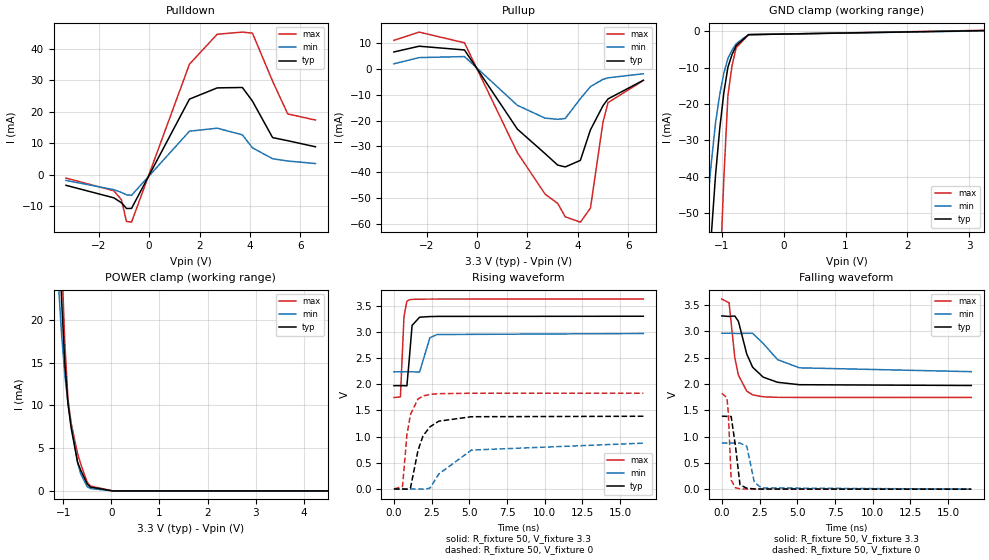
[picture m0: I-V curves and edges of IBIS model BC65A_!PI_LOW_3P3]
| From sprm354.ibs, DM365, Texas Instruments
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|   Model Cell BC65A_!PI_LOW_3P3
|BC1833DV65ATHYPBFZP_!PI_LOW_3P3
[Model]   BC65A_!PI_LOW_3P3
Model_type   I/O
Polarity   Non-Inverting
Enable   Active-Low
Vinl =  0.8V
Vinh =  2V
Cref =  15pF
Rref =  100.00M
Vref =  0V
Vmeas =  1.65
C_comp   1.512681p   1.336608p   1.607201p
[Model Spec]
Vinl   0.8V   0.8V   0.8V
Vinh   2V   2V   2V
[Temperature Range]   25   125   -40
[Voltage Range]   3.3   2.97   3.63
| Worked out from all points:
|   slope of the pulldown table from 0 to 0.495 V, typ, clamps not added: 56.1 ohm
|   slope of the pullup table from 0 to 0.495 V, typ, clamps not added: 64.3 ohm
|   GND clamp passes 1 mA (typ) near -0.57 V on its own axis
|   POWER clamp passes 1 mA (typ) near -0.52 V on its own axis
|   rising waveform, R_fixture 50, V_fixture 3.3: 20-80 % time 186ps typ, 268ps min, 141ps max; typ from 1.97 V to 3.3 V
|   rising waveform, R_fixture 50, V_fixture 0: 20-80 % time 866ps typ, 1.9ns min, 463ps max; typ from 0 V to 1.39 V
|   falling waveform, R_fixture 50, V_fixture 3.3: 20-80 % time 1.03ns typ, 1.61ns min, 559ps max; typ from 3.3 V to 1.97 V
|   falling waveform, R_fixture 50, V_fixture 0: 20-80 % time 211ps typ, 346ps min, 142ps max; typ from 1.39 V to 0 V
[POWER_clamp]
|   voltage   I(typ)   I(min)   I(max)
-3.3V     617.8mA    728.2mA    693.2mA
-1.1V     32.36mA    24.41mA    41.14mA
-1.033V   22.42mA    18.36mA    27.55mA
-966.7mV  15.04mA    13.64mA    17.42mA
-900mV    10.21mA    10.27mA    10.75mA
-833.3mV  7.343mA    7.736mA    7.918mA
-700mV    3.35mA     3.291mA    4.364mA
-633.3mV  2.402mA    1.963mA    3.125mA
-500mV    813.1uA    500.1uA    1.004mA
-433.3mV  446.7uA    279uA      570.4uA
33.33mV   0A         0A         0A
6.6V      0A         0A         0A
[Pulldown]
|   voltage   I(typ)   I(min)   I(max)
-3.3V     -3.312mA   -1.764mA   -1.021mA
-1.4V     -7.283mA   -4.687mA   -5.038mA
-1.1V     -8.83mA    -5.573mA   -7.893mA
-900mV    -10.65mA   -6.307mA   -14.74mA
-700mV    -10.64mA   -6.484mA   -15mA
1.6V      24.01mA    13.84mA    35.08mA
2.7V      27.57mA    14.8mA     44.57mA
3.7V      27.7mA     12.68mA    45.26mA
4.1V      23.38mA    8.578mA    44.92mA
4.9V      11.81mA    5.118mA    29.68mA
5.5V      10.83mA    4.397mA    19.31mA
6.6V      8.906mA    3.589mA    17.38mA
[Pullup]
|   voltage   I(typ)   I(min)   I(max)
-3.3V     6.54mA     1.969mA    11.03mA
-2.3V     8.757mA    4.357mA    14.22mA
-500mV    7.317mA    4.758mA    10.08mA
1.6V      -23.29mA   -14.09mA   -32.38mA
2.7V      -32.76mA   -19.04mA   -48.43mA
3.2V      -37.19mA   -19.48mA   -51.99mA
3.5V      -37.9mA    -19.18mA   -57.17mA
4.1V      -35.37mA   -11.52mA   -59.26mA
4.5V      -23.57mA   -6.848mA   -53.81mA
5V        -14.2mA    -4.028mA   -20.44mA
5.2V      -11.59mA   -3.459mA   -13.01mA
6.6V      -4.403mA   -1.883mA   -4.482mA
[GND_clamp]
|   voltage   I(typ)   I(min)   I(max)
-3.3V     -675.4mA   -720mA     -1.407A
-1.3V     -90.36mA   -60.41mA   -217.3mA
-1.233V   -72.63mA   -47.73mA   -178.1mA
-1.167V   -55.68mA   -35.96mA   -139.7mA
-1.1V     -39.52mA   -25.11mA   -102.1mA
-1.033V   -26.87mA   -17.46mA   -68.92mA
-966.7mV  -17mA      -11.58mA   -40.75mA
-900mV    -9.882mA   -7.454mA   -17.64mA
-833.3mV  -6.396mA   -5.18mA    -9.425mA
-766.7mV  -3.95mA    -3.425mA   -4.522mA
-566.7mV  -952.9uA   -925.9uA   -953.8uA
3.233V    154.8uA    91.52uA    247.5uA
[Ramp]
| variable   typ   min   max
dV/dt_f  0.7941831/1.024705n   0.4396363/1.616067n   1.127286/0.5580922n
dV/dt_r  0.8359851/0.8652909n  0.5292419/1.919135n   1.099152/0.4622589n
R_load = 50
[Rising Waveform]
R_fixture = 50
V_fixture = 3.3
V_fixture_min = 2.97
V_fixture_max = 3.63
|   time   V(typ)   V(min)   V(max)
0s        1.972V     2.235V     1.745V
432ps     1.972V     2.235V     1.758V
668ps     1.972V     2.235V     3.295V
860ps     1.968V     2.235V     3.58V
1.004ns   2.43V      2.235V     3.608V
1.204ns   3.121V     2.235V     3.618V
1.704ns   3.278V     2.234V     3.622V
2.384ns   3.29V      2.885V     3.623V
2.86ns    3.293V     2.947V     3.623V
16.54ns   3.296V     2.967V     3.624V
[Rising Waveform]
R_fixture = 50
V_fixture = 0
V_fixture_min = 0
V_fixture_max = 0
|   time   V(typ)   V(min)   V(max)
0s        8.912uV    -807.8nV   16.94uV
572ps     1.624uV    8.297uV    49.22mV
860ps     -3.219mV   6.647uV    1.026V
1.1ns     21.45mV    5.469uV    1.425V
1.596ns   734.4mV    -88.98uV   1.717V
1.928ns   1.012V     -2.883mV   1.775V
2.384ns   1.185V     13.6mV     1.805V
2.976ns   1.294V     285.9mV    1.819V
5.14ns    1.379V     742.6mV    1.827V
16.54ns   1.388V     874.8mV    1.827V
[Falling Waveform]
R_fixture = 50
V_fixture = 3.3
V_fixture_min = 2.97
V_fixture_max = 3.63
|   time   V(typ)   V(min)   V(max)
0s        3.296V     2.967V     3.616V
480ps     3.285V     2.967V     3.546V
860ps     3.294V     2.963V     2.501V
1.1ns     3.192V     2.961V     2.169V
1.652ns   2.57V      2.965V     1.865V
2.04ns    2.32V      2.965V     1.794V
2.74ns    2.131V     2.772V     1.757V
3.692ns   2.033V     2.465V     1.747V
5.14ns    1.987V     2.308V     1.745V
16.54ns   1.972V     2.235V     1.745V
[Falling Waveform]
R_fixture = 50
V_fixture = 0
V_fixture_min = 0
V_fixture_max = 0
|   time   V(typ)   V(min)   V(max)
0s        1.388V     877.8mV    1.822V
336ps     1.385V     877.7mV    1.743V
432ps     1.384V     877.7mV    1.441V
620ps     1.381V     877.2mV    172.2mV
908ps     809.5mV    875.9mV    24.9mV
1.204ns   82.39mV    876mV      6.734mV
1.652ns   18.4mV     819.3mV    1.196mV
2.152ns   5.684mV    135.4mV    262.7uV
2.62ns    2.536mV    24.01mV    81.97uV
16.54ns   172.5nV    123uV      146.2nV
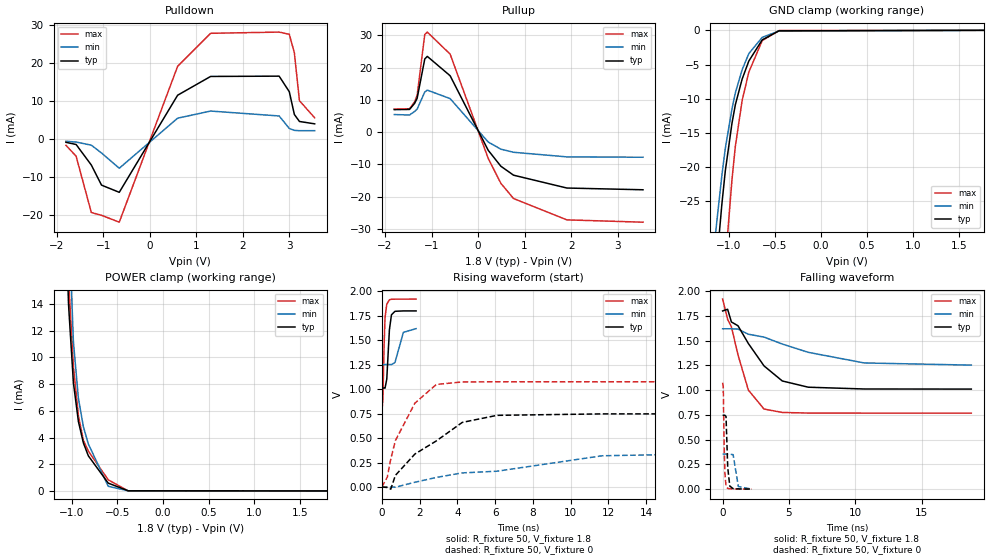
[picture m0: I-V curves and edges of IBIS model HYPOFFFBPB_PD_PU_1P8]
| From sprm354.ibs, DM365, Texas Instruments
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|   Model Cell HYPOFFFBPB_PD_PU_1P8
|BQ1865ACTHYPOFFFBPB_PD_PU_1P8
[Model]   HYPOFFFBPB_PD_PU_1P8
Model_type   I/O
Polarity   Non-Inverting
Enable   Active-Low
Vinl =  0.63V
Vinh =  1.17V
Cref =  15pF
Rref =  100.00M
Vref =  0V
Vmeas =  0.9
C_comp   2.929246p   0.7331204p   5.041237p
[Model Spec]
Vinl   0.63   0.567   0.6720
Vinh   1.17   1.053   1.2480
[Temperature Range]   25   125   -40
[Voltage Range]   1.8   1.62   1.92
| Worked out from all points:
|   slope of the pulldown table from 0 to 0.27 V, typ, clamps not added: 45.6 ohm
|   slope of the pullup table from 0 to 0.27 V, typ, clamps not added: 40.2 ohm
|   GND clamp passes 1 mA (typ) near -0.61 V on its own axis
|   POWER clamp passes 1 mA (typ) near -0.66 V on its own axis
|   rising waveform, R_fixture 50, V_fixture 1.8: 20-80 % time 135ps typ, 277ps min, 89.9ps max; typ from 1.01 V to 1.8 V
|   rising waveform, R_fixture 50, V_fixture 0: 20-80 % time 2.81ns typ, 7.38ns min, 1.37ns max; typ from 0 V to 0.747 V
|   falling waveform, R_fixture 50, V_fixture 1.8: 20-80 % time 2.44ns typ, 5.07ns min, 1.4ns max; typ from 1.8 V to 1.01 V
|   falling waveform, R_fixture 50, V_fixture 0: 20-80 % time 119ps typ, 187ps min, 86.5ps max; typ from 0.747 V to 0.002 V
[POWER_clamp]
|   voltage   I(typ)   I(min)   I(max)
-1.8V     4.267A     4.014A     4.507A
-1.073V   22.94mA    36.6mA     23.19mA
-1.055V   18.48mA    28.72mA    19.56mA
-1.036V   14.03mA    20.85mA    15.94mA
-1.018V   12.05mA    17.62mA    13.74mA
-981.8mV  8.098mA    11.16mA    9.336mA
-927.3mV  5.205mA    6.949mA    5.652mA
-872.7mV  3.599mA    4.815mA    3.801mA
-818.2mV  2.63mA     3.517mA    2.987mA
-600mV    583.6uA    346.4uA    830.5uA
-381.8mV  11.11uA    10.67uA    3.773uA
1.8V      342.4pA    2.655nA    261.8pA
[Pulldown]
|   voltage   I(typ)   I(min)   I(max)
-1.8V     -854.1uA   -575.1uA   -1.647mA
-1.582V   -1.423mA   -782.2uA   -4.502mA
-1.255V   -6.844mA   -1.605mA   -19.37mA
-1.036V   -12.14mA   -3.666mA   -20.1mA
-654.5mV  -14.04mA   -7.691mA   -21.92mA
600mV     11.57mA    5.514mA    19.2mA
1.309V    16.52mA    7.392mA    27.9mA
2.782V    16.6mA     6.099mA    28.22mA
3V        12.49mA    2.799mA    27.64mA
3.109V    6.495mA    2.299mA    22.76mA
3.218V    4.645mA    2.213mA    10.13mA
3.545V    4.02mA     2.213mA    5.614mA
[Pullup]
|   voltage   I(typ)   I(min)   I(max)
-1.8V     7.01mA     5.479mA    7.164mA
-1.473V   7.062mA    5.341mA    7.236mA
-1.364V   8.935mA    6.411mA    9.416mA
-1.309V   10.51mA    7.164mA    11.44mA
-1.145V   22.7mA     12.47mA    30.3mA
-1.091V   23.51mA    13.05mA    31.04mA
-600mV    17.51mA    10.42mA    24.21mA
218.2mV   -5.6mA     -3.035mA   -8.116mA
490.9mV   -10.55mA   -5.26mA    -15.85mA
763.6mV   -13.32mA   -6.218mA   -20.56mA
1.909V    -17.3mA    -7.642mA   -27.17mA
3.545V    -17.84mA   -7.757mA   -27.89mA
[GND_clamp]
|   voltage   I(typ)   I(min)   I(max)
-1.8V     -173.3mA   -141.2mA   -250.4mA
-1.182V   -42.82mA   -35.22mA   -67.09mA
-1.145V   -36.39mA   -30.05mA   -58.15mA
-1.073V   -25.36mA   -21.15mA   -41.64mA
-1.036V   -20.53mA   -17.24mA   -33.92mA
-963.6mV  -13.56mA   -11.46mA   -21.78mA
-927.3mV  -10.87mA   -9.137mA   -16.95mA
-854.5mV  -7.158mA   -5.788mA   -10.31mA
-781.8mV  -4.498mA   -3.413mA   -6.119mA
-636.4mV  -1.396mA   -1.026mA   -1.504mA
-454.5mV  -72.84uA   -97.18uA   -38.13uA
1.764V    314.5pA    50.88nA    191.3pA
[Ramp]
| variable   typ   min   max
dV/dt_f  0.4839599/2.485923n   0.2285221/5.27314n   0.7034606/1.494559n
dV/dt_r  0.4631262/2.870029n   0.2196685/7.65891n   0.665413/1.389446n
R_load = 50
[Rising Waveform]
R_fixture = 50
V_fixture = 1.8
V_fixture_min = 1.62
V_fixture_max = 1.92
|   time   V(typ)   V(min)   V(max)
0s        1.011V     1.251V     768.4mV
56ps      1.011V     1.251V     899.9mV
120ps     1.011V     1.251V     1.455V
168ps     1.01V      1.251V     1.73V
260ps     1.101V     1.251V     1.867V
400ps     1.606V     1.251V     1.913V
508ps     1.759V     1.25V      1.918V
696ps     1.795V     1.273V     1.919V
1.14ns    1.799V     1.58V      1.919V
1.812ns   1.799V     1.618V     1.92V
[Rising Waveform]
R_fixture = 50
V_fixture = 0
V_fixture_min = 0
V_fixture_max = 0
|   time   V(typ)   V(min)   V(max)
0s        120.7nV    100.4nV    188.8nV
288ps     -5.035mV   34.99uV    101.3mV
472ps     -22.16mV   82.34uV    285.5mV
716ps     118.7mV    -1.999mV   473.9mV
1.752ns   337.1mV    48.53mV    857mV
2.888ns   471.1mV    97.8mV     1.048V
4.26ns    659.9mV    144mV      1.073V
6.1ns     732mV      161.3mV    1.075V
11.67ns   746.9mV    319mV      1.075V
21.08ns   747mV      352.7mV    1.075V
[Falling Waveform]
R_fixture = 50
V_fixture = 1.8
V_fixture_min = 1.62
V_fixture_max = 1.92
|   time   V(typ)   V(min)   V(max)
0s        1.8V       1.62V      1.92V
376ps     1.817V     1.62V      1.715V
660ps     1.689V     1.62V      1.641V
1.16ns    1.65V      1.617V     1.355V
1.94ns    1.471V     1.565V     1.001V
3.12ns    1.245V     1.536V     809.4mV
4.496ns   1.093V     1.466V     775.2mV
6.456ns   1.03V      1.382V     769mV
10.67ns   1.012V     1.275V     768.4mV
18.74ns   1.011V     1.253V     768.4mV
[Falling Waveform]
R_fixture = 50
V_fixture = 0
V_fixture_min = 0
V_fixture_max = 0
|   time   V(typ)   V(min)   V(max)
0s        747mV      354.3mV    1.075V
48ps      746.9mV    354.3mV    1.029V
108ps     746.8mV    354.3mV    484.7mV
164ps     747.1mV    354.3mV    177.3mV
256ps     735.1mV    354.3mV    29.5mV
384ps     219.9mV    354.3mV    8.231mV
540ps     31.69mV    354.3mV    4.758mV
792ps     5.593mV    348.7mV    2.761mV
1.184ns   3.215mV    27.04mV    1.711mV
2.164ns   1.693mV    1.623mV    590.6uV
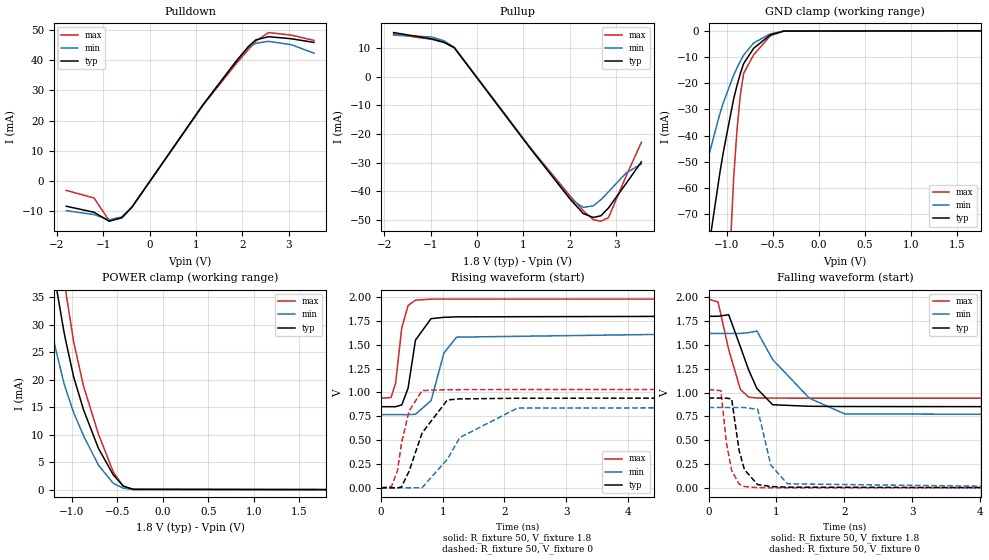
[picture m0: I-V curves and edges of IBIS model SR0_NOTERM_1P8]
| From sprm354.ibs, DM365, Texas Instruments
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|   Model Cell SR0_NOTERM_1P8
|SR0_NOTERM_1P8
[Model]   SR0_NOTERM_1P8
Model_type   I/O
Polarity   Non-Inverting
Enable   Active-Low
Vinl = 0.8V
Vinh = 2V
Cref =  15.0000pF
Rref =  100.0000M
Vref =  0V
Vmeas =  0.9
C_comp   3.009089p   2.23501p   3.950269p
[Model Spec]
Vinl   0.8V   0.8V   0.8V
Vinh   2V   2V   2V
[Temperature Range]   25   125   -40
[Voltage Range]   1.8   1.62   1.98
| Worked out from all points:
|   slope of the pulldown table from 0 to 0.27 V, typ, clamps not added: 44.1 ohm
|   slope of the pullup table from 0 to 0.27 V, typ, clamps not added: 45.3 ohm
|   GND clamp passes 1 mA (typ) near -0.50 V on its own axis
|   POWER clamp passes 1 mA (typ) near -0.46 V on its own axis
|   rising waveform, R_fixture 50, V_fixture 1.8: 20-80 % time 145ps typ, 215ps min, 110ps max; typ from 0.851 V to 1.8 V
|   rising waveform, R_fixture 50, V_fixture 0: 20-80 % time 334ps typ, 727ps min, 192ps max; typ from 0 V to 0.942 V
|   falling waveform, R_fixture 50, V_fixture 1.8: 20-80 % time 328ps typ, 648ps min, 213ps max; typ from 1.8 V to 0.851 V
|   falling waveform, R_fixture 50, V_fixture 0: 20-80 % time 148ps typ, 181ps min, 119ps max; typ from 0.942 V to 0 V
[POWER_clamp]
|   voltage   I(typ)   I(min)   I(max)
-1.8V     107.1mA    82.38mA    134mA
-1.327V   53.28mA    37.63mA    69.44mA
-1.182V   37.78mA    25.73mA    50.07mA
-1.091V   28.94mA    19.52mA    38.61mA
-1.073V   27.41mA    18.52mA    36.52mA
-981.8mV  20.5mA     14.01mA    26.9mA
-872.7mV  14.5mA     9.789mA    18.8mA
-709.1mV  7.513mA    4.451mA    10.09mA
-545.5mV  2.674mA    1.139mA    3.21mA
-436.4mV  654.9uA    255.5uA    594.4uA
-327.3mV  54.9uA     31.45uA    28.93uA
1.8V      5.504nA    118.5nA    1.898nA
[Pulldown]
|   voltage   I(typ)   I(min)   I(max)
-1.8V     -8.351mA   -9.832mA   -3.116mA
-1.2V     -10.35mA   -11.12mA   -5.615mA
-872.7mV  -13.35mA   -12.83mA   -13.13mA
-600mV    -12.16mA   -11.91mA   -12.18mA
-381.8mV  -8.669mA   -8.547mA   -8.669mA
1.145V    25.19mA    25.08mA    24.97mA
1.855V    39.42mA    39.58mA    38.69mA
2.127V    44.53mA    44.34mA    43.55mA
2.291V    46.79mA    45.65mA    46.35mA
2.564V    47.83mA    46.29mA    49.2mA
3.055V    47.15mA    45.17mA    48.35mA
3.545V    45.94mA    42.37mA    46.6mA
[Pullup]
|   voltage   I(typ)   I(min)   I(max)
-1.8V     15.34mA    14.46mA    14.83mA
-981.8mV  13.15mA    13.81mA    12.99mA
-709.1mV  11.92mA    12.48mA    11.95mA
-490.9mV  10.05mA    10.19mA    10.14mA
1.145V    -24.96mA   -24.69mA   -24.66mA
2.018V    -42.87mA   -42.71mA   -41.79mA
2.291V    -47.72mA   -45.58mA   -46.74mA
2.509V    -49.09mA   -45.01mA   -49.87mA
2.673V    -48.48mA   -42.88mA   -50.42mA
2.836V    -45.77mA   -40.16mA   -49.13mA
3.218V    -37.2mA    -33.54mA   -34.59mA
3.545V    -29.71mA   -30.45mA   -22.9mA
[GND_clamp]
|   voltage   I(typ)   I(min)   I(max)
-1.8V     -229.3mA   -132mA     -818.5mA
-1.436V   -139.1mA   -79.12mA   -490.7mA
-1.073V   -53.39mA   -31.17mA   -167.2mA
-1.036V   -45.75mA   -27.16mA   -136.8mA
-927.3mV  -26.08mA   -17mA      -56.49mA
-890.9mV  -20.9mA    -14.21mA   -38.02mA
-854.5mV  -16.38mA   -11.64mA   -24.6mA
-818.2mV  -12.5mA    -9.274mA   -16.24mA
-709.1mV  -6.663mA   -4.641mA   -9.158mA
-527.3mV  -1.534mA   -1.158mA   -1.867mA
-381.8mV  -101.4uA   -119.6uA   -85.85uA
1.764V    4.755nA    714.3nA    1.257nA
[Ramp]
| variable   typ   min   max
dV/dt_f  0.5831644/0.3322235n  0.5298923/0.6573559n  0.6335674/0.2161102n
dV/dt_r  0.5657631/0.3333447n  0.5057422/0.7275961n  0.6192225/0.1909312n
R_load = 50
[Rising Waveform]
R_fixture = 50
V_fixture = 1.8
V_fixture_min = 1.62
V_fixture_max = 1.98
|   time   V(typ)   V(min)   V(max)
0s        851mV      767.9mV    940.9mV
158.4ps   851mV      767.9mV    946.8mV
233.6ps   850.7mV    767.9mV    1.096V
334.4ps   869.9mV    767.9mV    1.681V
436.8ps   1.047V     767.8mV    1.913V
556.8ps   1.551V     771.6mV    1.969V
809.6ps   1.775V     914.9mV    1.98V
1.018ns   1.789V     1.414V     1.98V
1.224ns   1.794V     1.581V     1.98V
5.442ns   1.8V       1.618V     1.98V
[Rising Waveform]
R_fixture = 50
V_fixture = 0
V_fixture_min = 0
V_fixture_max = 0
|   time   V(typ)   V(min)   V(max)
0s        84.48nV    277.2nV    37.22nV
168ps     2.237uV    327.5nV    14.35mV
267.2ps   -912.2uV   33.84nV    185.5mV
328.8ps   8.615mV    -187.1nV   466.3mV
452ps     172.4mV    -197.5uV   803.8mV
662.4ps   573.8mV    85.31uV    1.02V
1.074ns   922.1mV    299.6mV    1.03V
1.275ns   932.8mV    527.2mV    1.03V
2.211ns   939.6mV    836.1mV    1.031V
6.525ns   942mV      841.2mV    1.031V
[Falling Waveform]
R_fixture = 50
V_fixture = 1.8
V_fixture_min = 1.62
V_fixture_max = 1.98
|   time   V(typ)   V(min)   V(max)
0s        1.8V       1.62V      1.98V
140ps     1.8V       1.62V      1.95V
296.8ps   1.816V     1.62V      1.45V
469.6ps   1.479V     1.62V      1.032V
590.4ps   1.237V     1.629V     951.5mV
712ps     1.042V     1.645V     942.7mV
944ps     872mV      1.346V     941.5mV
1.485ns   855.8mV    939.9mV    941.2mV
2.006ns   853.3mV    775.5mV    941mV
5.655ns   851mV      769.5mV    940.9mV
[Falling Waveform]
R_fixture = 50
V_fixture = 0
V_fixture_min = 0
V_fixture_max = 0
|   time   V(typ)   V(min)   V(max)
0s        942mV      842.8mV    1.031V
181.6ps   942mV      842.8mV    1.02V
262.4ps   941.7mV    842.8mV    476mV
340ps     933.1mV    842.8mV    183.6mV
449.6ps   392.9mV    842.8mV    39.74mV
528.8ps   190.3mV    842.8mV    14.25mV
723.2ps   34.23mV    823.8mV    2.064mV
916.8ps   14.11mV    239.2mV    823.4uV
1.16ns    7.674mV    42.35mV    299.4uV
5.76ns    76.37uV    1.62mV     32.52nV
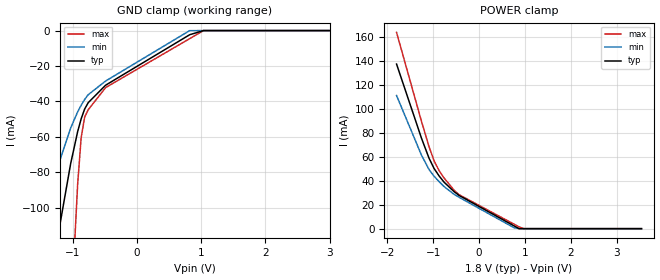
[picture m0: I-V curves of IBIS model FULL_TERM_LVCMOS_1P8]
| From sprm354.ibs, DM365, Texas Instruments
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|   Model Cell FULL_TERM_LVCMOS_1P8
|FULL_TERM_LVCMOS_1P8
[Model]   FULL_TERM_LVCMOS_1P8
Model_type   Input
Polarity   Non-Inverting
Vinl =  0.63
Vinh =  1.17
C_comp   3.009089p   2.23501p   3.950269p
[Model Spec]
Vinl   0.63   0.567   0.693
Vinh   1.17   1.053   1.287
[Temperature Range]   25   125   -40
[Voltage Range]   1.8   1.62   1.98
[POWER_clamp]
|   voltage   I(typ)   I(min)   I(max)
-1.8V     137.1mA    110.9mA    163.5mA
-1.255V   75.24mA    61.14mA    89.25mA
-1.091V   58.68mA    49.27mA    68.25mA
-981.8mV  50.15mA    43.66mA    56.55mA
-872.7mV  43.98mA    39.19mA    48.42mA
-763.6mV  38.74mA    35.09mA    42.25mA
-545.5mV  30.88mA    28.59mA    32.05mA
-436.4mV  27.7mA     26.15mA    28.32mA
763.6mV   2.335mA    781.1uA    3.756mA
872.7mV   0A         0A         1.482mA
981.8mV   0A         0A         0A
3.545V    0A         0A         0A
[GND_clamp]
|   voltage   I(typ)   I(min)   I(max)
-1.8V     -248.2mA   -152.9mA   -828.2mA
-1.418V   -158.5mA   -100.4mA   -490.9mA
-1.2V     -108.8mA   -72.75mA   -299.5mA
-1.036V   -75.06mA   -54.97mA   -163.6mA
-927.3mV  -57.04mA   -45.92mA   -86.79mA
-872.7mV  -49.83mA   -42.16mA   -60.5mA
-818.2mV  -44.29mA   -38.89mA   -48.85mA
-763.6mV  -40.74mA   -36.23mA   -44.74mA
-490.9mV  -30.82mA   -28.47mA   -32.17mA
818.2mV   -2.352mA   -40.93uA   -4.565mA
1.036V    0A         0A         0A
3.545V    0A         0A         0A
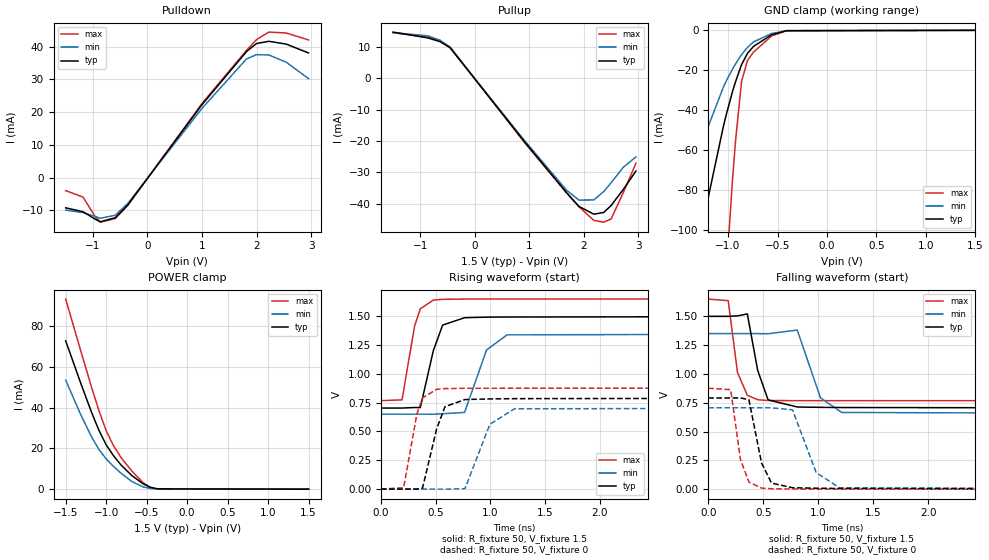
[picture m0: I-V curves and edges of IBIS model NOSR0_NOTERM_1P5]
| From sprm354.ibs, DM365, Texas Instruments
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|   Model Cell NOSR0_NOTERM_1P5
|NOSR0_NOTERM_1P5
[Model]   NOSR0_NOTERM_1P5
Model_type   I/O
Polarity   Non-Inverting
Enable   Active-Low
Vinl = 0.8V
Vinh = 2V
Cref =  15.0000pF
Rref =  100.0000M
Vref =  0V
Vmeas =  0.75
C_comp   3.047242p   2.257596p   4.009695p
[Model Spec]
Vinl   0.8V   0.8V   0.8V
Vinh   2V   2V   2V
[Temperature Range]   25   125   -40
[Voltage Range]   1.5   1.35   1.65
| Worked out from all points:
|   slope of the pulldown table from 0 to 0.225 V, typ, clamps not added: 43.5 ohm
|   slope of the pullup table from 0 to 0.225 V, typ, clamps not added: 44.5 ohm
|   GND clamp passes 1 mA (typ) near -0.50 V on its own axis
|   POWER clamp passes 1 mA (typ) near -0.46 V on its own axis
|   rising waveform, R_fixture 50, V_fixture 1.5: 20-80 % time 114ps typ, 148ps min, 97.1ps max; typ from 0.703 V to 1.5 V
|   rising waveform, R_fixture 50, V_fixture 0: 20-80 % time 119ps typ, 158ps min, 101ps max; typ from 0 V to 0.792 V
|   falling waveform, R_fixture 50, V_fixture 1.5: 20-80 % time 90.2ps typ, 126ps min, 77.7ps max; typ from 1.5 V to 0.703 V
|   falling waveform, R_fixture 50, V_fixture 0: 20-80 % time 92.9ps typ, 151ps min, 76.2ps max; typ from 0.792 V to 0 V
[POWER_clamp]
|   voltage   I(typ)   I(min)   I(max)
-1.5V     72.7mA     53.44mA    93.18mA
-1.318V   52.38mA    36.88mA    68.36mA
-1.182V   37.83mA    25.73mA    50.18mA
-1.091V   29.01mA    19.56mA    38.72mA
-1V       21.75mA    14.84mA    28.68mA
-909.1mV  16.39mA    11.15mA    21.28mA
-818.2mV  11.93mA    7.901mA    15.6mA
-681.8mV  6.623mA    3.713mA    8.833mA
-545.5mV  2.678mA    1.141mA    3.213mA
-454.5mV  887.8uA    343.9uA    858.6uA
-363.6mV  140.3uA    66.33uA    91.97uA
1.5V      4.339nA    108.4nA    952.4pA
[Pulldown]
|   voltage   I(typ)   I(min)   I(max)
-1.5V     -9.235mA   -9.935mA   -3.974mA
-1.182V   -10.44mA   -10.7mA    -5.949mA
-954.5mV  -12.72mA   -11.86mA   -12.01mA
-863.6mV  -13.5mA    -12.42mA   -13.62mA
-590.9mV  -12.24mA   -11.5mA    -12.52mA
-363.6mV  -8.405mA   -7.956mA   -8.569mA
1V        22.28mA    21.15mA    22.64mA
1.818V    38.51mA    36.26mA    38.89mA
2V        40.95mA    37.55mA    42.14mA
2.227V    41.63mA    37.44mA    44.44mA
2.545V    40.77mA    35.25mA    44.16mA
2.955V    38.06mA    30.23mA    42.04mA
[Pullup]
|   voltage   I(typ)   I(min)   I(max)
-1.5V     14.7mA     14.52mA    14.5mA
-863.6mV  12.86mA    13.51mA    13.07mA
-636.4mV  11.64mA    12.11mA    11.96mA
-454.5mV  9.734mA    9.774mA    10.01mA
909.1mV   -20.18mA   -19.79mA   -20.43mA
1.682V    -36.4mA    -35.65mA   -36.52mA
1.909V    -40.82mA   -38.81mA   -40.93mA
2.182V    -43.3mA    -38.76mA   -45.27mA
2.364V    -42.76mA   -36.1mA    -45.85mA
2.5V      -40.54mA   -33.29mA   -44.83mA
2.727V    -35.31mA   -28.29mA   -36.29mA
2.955V    -29.56mA   -25.07mA   -27.07mA
[GND_clamp]
|   voltage   I(typ)   I(min)   I(max)
-1.5V     -154.8mA   -88.21mA   -548.3mA
-1.379V   -125mA     -70.97mA   -438.6mA
-1.045V   -47.59mA   -28.12mA   -144.3mA
-1.015V   -41.63mA   -25.03mA   -120mA
-954.5mV  -30.51mA   -19.31mA   -74.42mA
-924.2mV  -25.71mA   -16.8mA    -55.35mA
-863.6mV  -17.19mA   -12.18mA   -25.62mA
-803mV    -11.46mA   -8.491mA   -15.01mA
-742.4mV  -8.023mA   -5.77mA    -10.9mA
-560.6mV  -2.222mA   -1.606mA   -2.834mA
-409.1mV  -188.4uA   -199.7uA   -167.9uA
1.5V      4.339nA    679.1nA    663.7pA
[Ramp]
| variable   typ   min   max
dV/dt_f  0.4953443/91.53772p   0.4415986/0.1308864n  0.5436444/78.38737p
dV/dt_r  0.4770077/0.1186069n  0.4260954/0.1570559n   0.527506/0.1010439n
R_load = 50
[Rising Waveform]
R_fixture = 50
V_fixture = 1.5
V_fixture_min = 1.35
V_fixture_max = 1.65
|   time   V(typ)   V(min)   V(max)
0s        703.4mV    650.3mV    767.7mV
193.6ps   703.4mV    650.3mV    774.7mV
308ps     708.1mV    650.3mV    1.415V
360.8ps   707.1mV    650.3mV    1.566V
480ps     1.203V     650mV      1.641V
564.8ps   1.424V     654.1mV    1.648V
765.6ps   1.488V     665.5mV    1.65V
966.4ps   1.493V     1.208V     1.65V
1.154ns   1.494V     1.339V     1.65V
5.458ns   1.5V       1.349V     1.65V
[Rising Waveform]
R_fixture = 50
V_fixture = 0
V_fixture_min = 0
V_fixture_max = 0
|   time   V(typ)   V(min)   V(max)
0s        69.34nV    280.7nV    23.27nV
208ps     134.1nV    341.3nV    10.95mV
329.6ps   -263.7uV   -908.8nV   653.3mV
380.8ps   8.178mV    1.899uV    791.1mV
510.4ps   524.3mV    -785.3uV   866.5mV
586.4ps   715.3mV    -1.041mV   872.4mV
768.8ps   777.3mV    3.121mV    874.8mV
996.8ps   782.7mV    562.3mV    875.3mV
1.222ns   785.1mV    697.2mV    875.5mV
6.393ns   791.6mV    705mV      875.8mV
[Falling Waveform]
R_fixture = 50
V_fixture = 1.5
V_fixture_min = 1.35
V_fixture_max = 1.65
|   time   V(typ)   V(min)   V(max)
0s        1.5V       1.35V      1.65V
181.6ps   1.5V       1.35V      1.636V
265.6ps   1.504V     1.35V      1.014V
355.2ps   1.521V     1.35V      814.6mV
449.6ps   1.03V      1.35V      776.1mV
544ps     775.1mV    1.349V     769.5mV
808.8ps   713.1mV    1.381V     768.1mV
1.02ns    710.1mV    792.4mV    768mV
1.214ns   708.5mV    665.8mV    768mV
5.678ns   703.5mV    651.7mV    767.7mV
[Falling Waveform]
R_fixture = 50
V_fixture = 0
V_fixture_min = 0
V_fixture_max = 0
|   time   V(typ)   V(min)   V(max)
0s        791.6mV    706.4mV    875.8mV
204ps     791.6mV    706.4mV    863.5mV
292.8ps   791.5mV    706.4mV    257.7mV
369.6ps   777.3mV    706.4mV    61.28mV
484ps     228.5mV    706.4mV    9.508mV
575.2ps   52.57mV    706.1mV    3.427mV
765.6ps   12.44mV    688.9mV    1.302mV
980.8ps   8.313mV    143.8mV    619.9uV
1.194ns   6.163mV    10.95mV    287.5uV
6.114ns   46.58uV    1.35mV     20.64nV
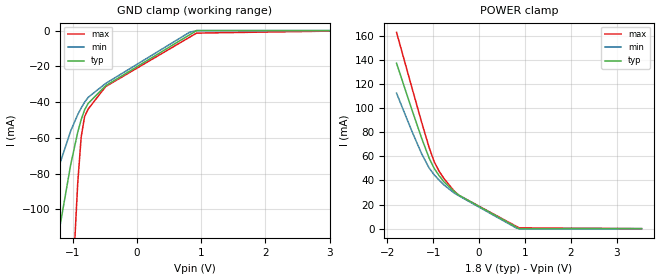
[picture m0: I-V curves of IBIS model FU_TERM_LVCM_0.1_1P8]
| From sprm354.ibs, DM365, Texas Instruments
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|   Model Cell FU_TERM_LVCM_0.1_1P8
|FULL_TERM_LVCMOS_0.1_1P8
[Model]   FU_TERM_LVCM_0.1_1P8
Model_type   Input
Polarity   Non-Inverting
Vinl =  0.63
Vinh =  1.17
C_comp   3.009089p   2.23501p   3.95018p
[Model Spec]
Vinl   0.63   0.595   0.665
Vinh   1.17   1.105   1.235
[Temperature Range]   25   125   -40
[Voltage Range]   1.8   1.7   1.9
[POWER_clamp]
|   voltage   I(typ)   I(min)   I(max)
-1.8V     137.1mA    112.3mA    162.7mA
-1.473V   99.49mA    81.47mA    118mA
-1.255V   75.24mA    62.3mA     88.5mA
-1.091V   58.68mA    50.39mA    67.5mA
-981.8mV  50.15mA    44.76mA    55.8mA
-872.7mV  43.98mA    40.27mA    47.67mA
-763.6mV  38.74mA    36.16mA    41.49mA
-545.5mV  30.88mA    29.61mA    31.29mA
-436.4mV  27.7mA     27.16mA    27.55mA
818.2mV   1.165mA    454.4uA    1.822mA
872.7mV   0A         0A         683.8uA
3.545V    0A         0A         0A
[GND_clamp]
|   voltage   I(typ)   I(min)   I(max)
-1.8V     -248.2mA   -154mA     -827.4mA
-1.418V   -158.5mA   -101.6mA   -490.2mA
-1.2V     -108.8mA   -73.97mA   -298.7mA
-1.036V   -75.06mA   -56.15mA   -162.8mA
-927.3mV  -57.04mA   -47.09mA   -85.99mA
-872.7mV  -49.83mA   -43.32mA   -59.68mA
-818.2mV  -44.29mA   -40.04mA   -48mA
-763.6mV  -40.74mA   -37.37mA   -43.89mA
-490.9mV  -30.82mA   -29.56mA   -31.32mA
818.2mV   -2.352mA   -925.3uA   -3.69mA
927.3mV   -5.951uA   0A         -1.407mA
3.545V    0A         0A         0A
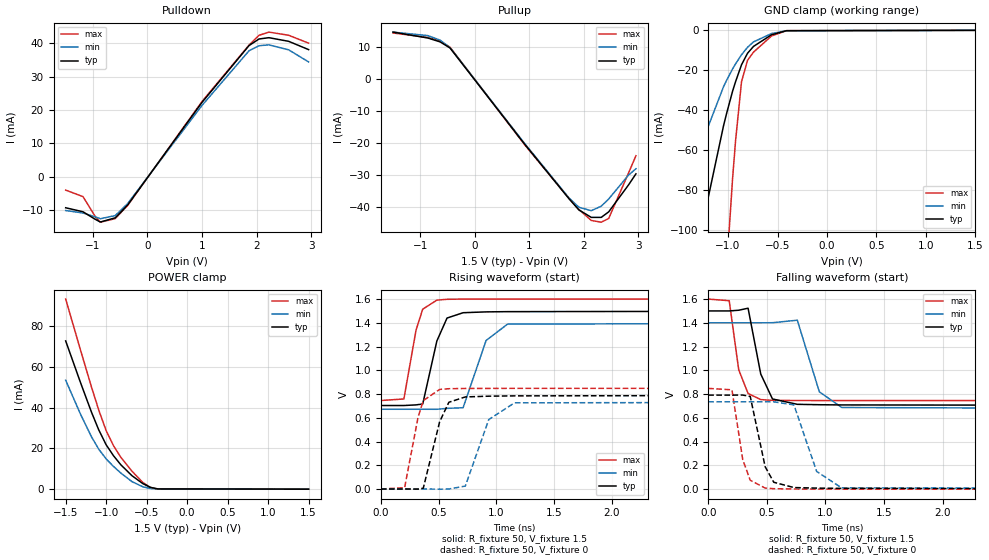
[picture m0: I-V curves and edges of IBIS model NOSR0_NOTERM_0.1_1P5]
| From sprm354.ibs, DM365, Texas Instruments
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|   Model Cell NOSR0_NOTERM_0.1_1P5
|NOSR0_NOTERM_0.1_1P5
[Model]   NOSR0_NOTERM_0.1_1P5
Model_type   I/O
Polarity   Non-Inverting
Enable   Active-Low
Vinl = 0.8V
Vinh = 2V
Cref =  15.0000pF
Rref =  100.0000M
Vref =  0V
Vmeas =  0.75
C_comp   3.047242p   2.257596p   4.009695p
[Model Spec]
Vinl   0.8V   0.8V   0.8V
Vinh   2V   2V   2V
[Temperature Range]   25   125   -40
[Voltage Range]   1.5   1.4   1.6
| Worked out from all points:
|   slope of the pulldown table from 0 to 0.225 V, typ, clamps not added: 43.5 ohm
|   slope of the pullup table from 0 to 0.225 V, typ, clamps not added: 44.5 ohm
|   GND clamp passes 1 mA (typ) near -0.50 V on its own axis
|   POWER clamp passes 1 mA (typ) near -0.46 V on its own axis
|   rising waveform, R_fixture 50, V_fixture 1.5: 20-80 % time 114ps typ, 147ps min, 98ps max; typ from 0.703 V to 1.5 V
|   rising waveform, R_fixture 50, V_fixture 0: 20-80 % time 119ps typ, 155ps min, 102ps max; typ from 0 V to 0.792 V
|   falling waveform, R_fixture 50, V_fixture 1.5: 20-80 % time 90.1ps typ, 119ps min, 78.6ps max; typ from 1.5 V to 0.703 V
|   falling waveform, R_fixture 50, V_fixture 0: 20-80 % time 92.8ps typ, 140ps min, 78ps max; typ from 0.792 V to 0 V
[POWER_clamp]
|   voltage   I(typ)   I(min)   I(max)
-1.5V     72.7mA     53.42mA    93.21mA
-1.318V   52.38mA    36.87mA    68.38mA
-1.182V   37.83mA    25.73mA    50.19mA
-1.091V   29.01mA    19.56mA    38.73mA
-1V       21.75mA    14.83mA    28.69mA
-909.1mV  16.39mA    11.14mA    21.29mA
-818.2mV  11.93mA    7.898mA    15.6mA
-681.8mV  6.623mA    3.712mA    8.836mA
-545.5mV  2.678mA    1.14mA     3.213mA
-454.5mV  887.8uA    343.9uA    858.4uA
-363.6mV  140.3uA    66.34uA    91.92uA
1.5V      4.339nA    110.3nA    858.8pA
[Pulldown]
|   voltage   I(typ)   I(min)   I(max)
-1.5V     -9.235mA   -10.05mA   -3.95mA
-1.182V   -10.44mA   -10.8mA    -5.906mA
-954.5mV  -12.72mA   -11.97mA   -11.94mA
-863.6mV  -13.5mA    -12.52mA   -13.55mA
-590.9mV  -12.24mA   -11.57mA   -12.48mA
-363.6mV  -8.405mA   -8.003mA   -8.542mA
1V        22.28mA    21.36mA    22.53mA
1.864V    39.29mA    37.74mA    39.44mA
2.045V    41.23mA    39.22mA    42.33mA
2.227V    41.63mA    39.48mA    43.3mA
2.591V    40.53mA    37.98mA    42.34mA
2.955V    38.06mA    34.38mA    39.99mA
[Pullup]
|   voltage   I(typ)   I(min)   I(max)
-1.5V     14.7mA     14.69mA    14.42mA
-863.6mV  12.86mA    13.61mA    13.02mA
-636.4mV  11.64mA    12.19mA    11.92mA
-454.5mV  9.734mA    9.834mA    9.982mA
909.1mV   -20.18mA   -19.98mA   -20.36mA
1.727V    -37.31mA   -37.08mA   -37.22mA
1.909V    -40.82mA   -39.99mA   -40.7mA
2.136V    -43.15mA   -41.06mA   -44.11mA
2.318V    -43.15mA   -39.66mA   -44.65mA
2.455V    -41.43mA   -37.41mA   -43.5mA
2.818V    -33.04mA   -29.95mA   -29.35mA
2.955V    -29.56mA   -27.97mA   -23.91mA
[GND_clamp]
|   voltage   I(typ)   I(min)   I(max)
-1.5V     -154.8mA   -88.21mA   -548.3mA
-1.379V   -125mA     -70.97mA   -438.6mA
-1.045V   -47.59mA   -28.12mA   -144.3mA
-1.015V   -41.63mA   -25.04mA   -120mA
-954.5mV  -30.51mA   -19.31mA   -74.41mA
-924.2mV  -25.71mA   -16.8mA    -55.35mA
-863.6mV  -17.19mA   -12.18mA   -25.62mA
-803mV    -11.46mA   -8.492mA   -15mA
-742.4mV  -8.023mA   -5.771mA   -10.89mA
-560.6mV  -2.222mA   -1.607mA   -2.833mA
-409.1mV  -188.4uA   -199.8uA   -167.8uA
1.5V      4.339nA    282.3nA    668.4pA
[Ramp]
| variable   typ   min   max
dV/dt_f  0.4953443/91.53772p   0.4585637/0.1236269n  0.5274379/79.4399p
dV/dt_r  0.4770077/0.1186069n  0.4434774/0.1541188n  0.5108627/0.1020291n
R_load = 50
[Rising Waveform]
R_fixture = 50
V_fixture = 1.5
V_fixture_min = 1.4
V_fixture_max = 1.6
|   time   V(typ)   V(min)   V(max)
0s        703.4mV    671.8mV    745.7mV
199.2ps   703.4mV    671.8mV    758.4mV
304.8ps   708.6mV    671.8mV    1.34V
362.4ps   716.2mV    671.8mV    1.515V
484.8ps   1.247V     671.6mV    1.591V
572.8ps   1.44V      679.4mV    1.598V
712ps     1.485V     684.7mV    1.6V
911.2ps   1.492V     1.251V     1.6V
1.097ns   1.494V     1.389V     1.6V
5.362ns   1.5V       1.399V     1.6V
[Rising Waveform]
R_fixture = 50
V_fixture = 0
V_fixture_min = 0
V_fixture_max = 0
|   time   V(typ)   V(min)   V(max)
0s        69.34nV    279.2nV    22nV
205.6ps   -6.812uV   351.8nV    11.43mV
322.4ps   -438.7uV   834.6nV    606.3mV
367.2ps   6.995mV    2.211uV    744.8mV
508.8ps   566.5mV    -1.21mV    839mV
588.8ps   730.7mV    172.6uV    844.9mV
731.2ps   775.7mV    24.87mV    846.9mV
934.4ps   782mV      585.3mV    847.5mV
1.157ns   784.6mV    725.9mV    847.7mV
6.274ns   791.6mV    734mV      848.1mV
[Falling Waveform]
R_fixture = 50
V_fixture = 1.5
V_fixture_min = 1.4
V_fixture_max = 1.6
|   time   V(typ)   V(min)   V(max)
0s        1.5V       1.4V       1.6V
179.2ps   1.5V       1.4V       1.586V
260ps     1.506V     1.4V       1.005V
340ps     1.523V     1.4V       805mV
448ps     969.2mV    1.4V       754.1mV
548ps     759.3mV    1.401V     747.3mV
760ps     714.1mV    1.422V     746.1mV
948ps     710.7mV    819.3mV    746mV
1.14ns    708.9mV    687.2mV    746mV
5.559ns   703.5mV    673.2mV    745.7mV
[Falling Waveform]
R_fixture = 50
V_fixture = 0
V_fixture_min = 0
V_fixture_max = 0
|   time   V(typ)   V(min)   V(max)
0s        791.6mV    735.4mV    848.1mV
202.4ps   791.6mV    735.4mV    836.2mV
294.4ps   792.1mV    735.4mV    248.8mV
358.4ps   780.4mV    735.4mV    74.89mV
485.6ps   189.1mV    735.4mV    9.222mV
559.2ps   58.09mV    735.1mV    3.878mV
731.2ps   13.57mV    709.3mV    1.447mV
924.8ps   8.916mV    149.7mV    751.5uV
1.137ns   6.589mV    11.31mV    362.2uV
6.02ns    50.8uV     1.401mV    23.19nV
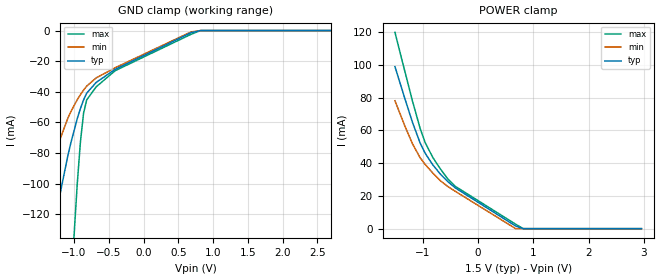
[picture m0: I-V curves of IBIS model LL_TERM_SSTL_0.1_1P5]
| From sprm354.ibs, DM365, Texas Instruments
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|   Model Cell LL_TERM_SSTL_0.1_1P5
|FULL_TERM_SSTL_0.1_1P5
[Model]   LL_TERM_SSTL_0.1_1P5
Model_type   Input
Polarity   Non-Inverting
Vinl =  0.65
Vinh =  0.85
C_comp   3.047242p   2.257596p   4.009695p
[Model Spec]
Vinl   0.65   0.6   0.7
Vinh   0.85   0.8   0.9
[Temperature Range]   25   125   -40
[Voltage Range]   1.5   1.4   1.6
[POWER_clamp]
|   voltage   I(typ)   I(min)   I(max)
-1.5V     98.88mA    78.03mA    119.8mA
-1.318V   79.04mA    62.38mA    95.54mA
-1.182V   64.76mA    51.71mA    77.68mA
-1.045V   52.24mA    43.28mA    61.2mA
-954.5mV  46.08mA    39.21mA    52.58mA
-818.2mV  39.02mA    34.03mA    43.57mA
-681.8mV  33.4mA     29.34mA    36.6mA
-545.5mV  28.72mA    25.74mA    30.34mA
-409.1mV  24.86mA    22.78mA    25.82mA
681.8mV   1.59mA     0A         2.702mA
818.2mV   0A         0A         0A
2.955V    0A         0A         0A
[GND_clamp]
|   voltage   I(typ)   I(min)   I(max)
-1.5V     -173.6mA   -107.8mA   -559.5mA
-1.091V   -82.02mA   -57.37mA   -203.7mA
-1.045V   -73.16mA   -52.87mA   -167.1mA
-954.5mV  -57.59mA   -45.15mA   -100.4mA
-909.1mV  -51mA      -41.86mA   -73.11mA
-863.6mV  -45.32mA   -38.9mA    -54mA
-818.2mV  -40.85mA   -36.26mA   -45.26mA
-681.8mV  -33.85mA   -30.9mA    -36.74mA
-409.1mV  -25.29mA   -24.28mA   -26.2mA
681.8mV   -1.39mA    -897.4uA   -2.457mA
818.2mV   0A         0A         0A
2.955V    0A         0A         0A
